VERSION 5.7 ;
  NOWIREEXTENSIONATPIN ON ;
  DIVIDERCHAR "/" ;
  BUSBITCHARS "[]" ;
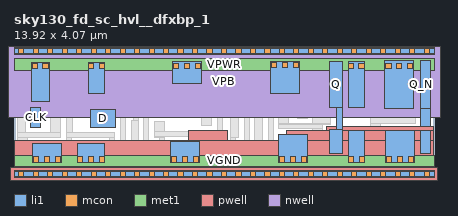
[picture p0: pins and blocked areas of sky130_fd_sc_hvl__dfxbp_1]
MACRO sky130_fd_sc_hvl__dfxbp_1
  CLASS BLOCK ;
  FOREIGN sky130_fd_sc_hvl__dfxbp_1 ;
  ORIGIN 0.000 0.000 ;
  SIZE 13.920 BY 4.070 ;
  PIN CLK
    ANTENNAGATEAREA 0.585000 ;
    PORT
      LAYER li1 ;
        RECT 0.560 1.550 0.890 2.220 ;
    END
  END CLK
  PIN D
    ANTENNAGATEAREA 0.420000 ;
    PORT
      LAYER li1 ;
        RECT 2.525 1.545 3.350 2.125 ;
    END
  END D
  PIN VGND
    USE GROUND ;
    PORT
      LAYER li1 ;
        RECT 0.620 0.365 1.570 1.020 ;
        RECT 2.100 0.365 2.990 1.015 ;
        RECT 5.185 0.365 6.135 1.065 ;
        RECT 8.775 0.365 9.725 1.325 ;
        RECT 11.070 0.365 11.625 1.485 ;
        RECT 12.315 0.365 13.265 1.485 ;
      LAYER mcon ;
        RECT 0.650 0.395 0.820 0.565 ;
        RECT 1.010 0.395 1.180 0.565 ;
        RECT 1.370 0.395 1.540 0.565 ;
        RECT 2.100 0.395 2.270 0.565 ;
        RECT 2.460 0.395 2.630 0.565 ;
        RECT 2.820 0.395 2.990 0.565 ;
        RECT 5.215 0.395 5.385 0.565 ;
        RECT 5.575 0.395 5.745 0.565 ;
        RECT 5.935 0.395 6.105 0.565 ;
        RECT 8.805 0.395 8.975 0.565 ;
        RECT 9.165 0.395 9.335 0.565 ;
        RECT 9.525 0.395 9.695 0.565 ;
        RECT 11.080 0.395 11.250 0.565 ;
        RECT 11.440 0.395 11.610 0.565 ;
        RECT 12.345 0.395 12.515 0.565 ;
        RECT 12.705 0.395 12.875 0.565 ;
        RECT 13.065 0.395 13.235 0.565 ;
      LAYER met1 ;
        RECT 0.000 0.255 13.920 0.625 ;
    END
  END VGND
  PIN VNB
    ANTENNADIFFAREA 2.366400 ;
    PORT
      LAYER pwell ;
        RECT 10.365 1.435 13.900 1.575 ;
        RECT 0.020 1.105 2.110 1.110 ;
        RECT 5.795 1.105 7.085 1.435 ;
        RECT 9.035 1.105 13.900 1.435 ;
        RECT 0.020 0.215 13.900 1.105 ;
        RECT -0.130 -0.215 14.050 0.215 ;
      LAYER li1 ;
        RECT 0.000 -0.085 13.920 0.085 ;
      LAYER mcon ;
        RECT 0.155 -0.085 0.325 0.085 ;
        RECT 0.635 -0.085 0.805 0.085 ;
        RECT 1.115 -0.085 1.285 0.085 ;
        RECT 1.595 -0.085 1.765 0.085 ;
        RECT 2.075 -0.085 2.245 0.085 ;
        RECT 2.555 -0.085 2.725 0.085 ;
        RECT 3.035 -0.085 3.205 0.085 ;
        RECT 3.515 -0.085 3.685 0.085 ;
        RECT 3.995 -0.085 4.165 0.085 ;
        RECT 4.475 -0.085 4.645 0.085 ;
        RECT 4.955 -0.085 5.125 0.085 ;
        RECT 5.435 -0.085 5.605 0.085 ;
        RECT 5.915 -0.085 6.085 0.085 ;
        RECT 6.395 -0.085 6.565 0.085 ;
        RECT 6.875 -0.085 7.045 0.085 ;
        RECT 7.355 -0.085 7.525 0.085 ;
        RECT 7.835 -0.085 8.005 0.085 ;
        RECT 8.315 -0.085 8.485 0.085 ;
        RECT 8.795 -0.085 8.965 0.085 ;
        RECT 9.275 -0.085 9.445 0.085 ;
        RECT 9.755 -0.085 9.925 0.085 ;
        RECT 10.235 -0.085 10.405 0.085 ;
        RECT 10.715 -0.085 10.885 0.085 ;
        RECT 11.195 -0.085 11.365 0.085 ;
        RECT 11.675 -0.085 11.845 0.085 ;
        RECT 12.155 -0.085 12.325 0.085 ;
        RECT 12.635 -0.085 12.805 0.085 ;
        RECT 13.115 -0.085 13.285 0.085 ;
        RECT 13.595 -0.085 13.765 0.085 ;
      LAYER met1 ;
        RECT 0.000 -0.115 13.920 0.115 ;
    END
  END VNB
  PIN VPB
    ANTENNADIFFAREA 2.366400 ;
    PORT
      LAYER nwell ;
        RECT -0.330 1.885 14.250 4.485 ;
      LAYER li1 ;
        RECT 0.000 3.985 13.920 4.155 ;
      LAYER mcon ;
        RECT 0.155 3.985 0.325 4.155 ;
        RECT 0.635 3.985 0.805 4.155 ;
        RECT 1.115 3.985 1.285 4.155 ;
        RECT 1.595 3.985 1.765 4.155 ;
        RECT 2.075 3.985 2.245 4.155 ;
        RECT 2.555 3.985 2.725 4.155 ;
        RECT 3.035 3.985 3.205 4.155 ;
        RECT 3.515 3.985 3.685 4.155 ;
        RECT 3.995 3.985 4.165 4.155 ;
        RECT 4.475 3.985 4.645 4.155 ;
        RECT 4.955 3.985 5.125 4.155 ;
        RECT 5.435 3.985 5.605 4.155 ;
        RECT 5.915 3.985 6.085 4.155 ;
        RECT 6.395 3.985 6.565 4.155 ;
        RECT 6.875 3.985 7.045 4.155 ;
        RECT 7.355 3.985 7.525 4.155 ;
        RECT 7.835 3.985 8.005 4.155 ;
        RECT 8.315 3.985 8.485 4.155 ;
        RECT 8.795 3.985 8.965 4.155 ;
        RECT 9.275 3.985 9.445 4.155 ;
        RECT 9.755 3.985 9.925 4.155 ;
        RECT 10.235 3.985 10.405 4.155 ;
        RECT 10.715 3.985 10.885 4.155 ;
        RECT 11.195 3.985 11.365 4.155 ;
        RECT 11.675 3.985 11.845 4.155 ;
        RECT 12.155 3.985 12.325 4.155 ;
        RECT 12.635 3.985 12.805 4.155 ;
        RECT 13.115 3.985 13.285 4.155 ;
        RECT 13.595 3.985 13.765 4.155 ;
      LAYER met1 ;
        RECT 0.000 3.955 13.920 4.185 ;
    END
  END VPB
  PIN VPWR
    USE POWER ;
    PORT
      LAYER li1 ;
        RECT 0.570 2.400 1.160 3.705 ;
        RECT 2.470 2.655 3.000 3.705 ;
        RECT 5.265 2.985 6.215 3.715 ;
        RECT 8.505 2.675 9.455 3.715 ;
        RECT 11.070 2.195 11.605 3.735 ;
        RECT 12.295 2.175 13.245 3.755 ;
      LAYER mcon ;
        RECT 0.600 3.505 0.770 3.675 ;
        RECT 0.960 3.505 1.130 3.675 ;
        RECT 2.470 3.505 2.640 3.675 ;
        RECT 2.830 3.505 3.000 3.675 ;
        RECT 5.295 3.505 5.465 3.675 ;
        RECT 5.655 3.505 5.825 3.675 ;
        RECT 6.015 3.505 6.185 3.675 ;
        RECT 8.535 3.515 8.705 3.685 ;
        RECT 8.895 3.515 9.065 3.685 ;
        RECT 9.255 3.515 9.425 3.685 ;
        RECT 11.070 3.505 11.240 3.675 ;
        RECT 11.430 3.505 11.600 3.675 ;
        RECT 12.325 3.505 12.495 3.675 ;
        RECT 12.685 3.505 12.855 3.675 ;
        RECT 13.045 3.505 13.215 3.675 ;
      LAYER met1 ;
        RECT 0.000 3.445 13.920 3.815 ;
    END
  END VPWR
  PIN Q
    ANTENNADIFFAREA 0.596250 ;
    PORT
      LAYER li1 ;
        RECT 10.455 2.195 10.890 3.735 ;
        RECT 10.685 1.465 10.890 2.195 ;
        RECT 10.455 0.675 10.890 1.465 ;
    END
  END Q
  PIN Q_N
    ANTENNADIFFAREA 0.626250 ;
    PORT
      LAYER li1 ;
        RECT 13.460 2.175 13.810 3.755 ;
        RECT 13.480 0.675 13.810 2.175 ;
    END
  END Q_N
  OBS
      LAYER li1 ;
        RECT 6.395 3.635 8.245 3.805 ;
        RECT 1.340 3.410 2.290 3.580 ;
        RECT 0.110 1.370 0.380 3.230 ;
        RECT 1.340 1.870 1.510 3.410 ;
        RECT 1.690 2.400 1.940 3.230 ;
        RECT 1.215 1.370 1.545 1.870 ;
        RECT 0.110 1.200 1.545 1.370 ;
        RECT 1.750 1.365 1.940 2.400 ;
        RECT 2.120 2.475 2.290 3.410 ;
        RECT 3.180 3.335 5.085 3.505 ;
        RECT 3.180 2.475 3.350 3.335 ;
        RECT 2.120 2.305 3.350 2.475 ;
        RECT 3.530 2.655 3.770 3.155 ;
        RECT 0.110 0.540 0.440 1.200 ;
        RECT 1.750 1.195 3.340 1.365 ;
        RECT 1.750 0.520 1.920 1.195 ;
        RECT 3.170 0.435 3.340 1.195 ;
        RECT 3.530 0.935 3.700 2.655 ;
        RECT 3.950 1.785 4.120 3.335 ;
        RECT 3.880 1.115 4.120 1.785 ;
        RECT 4.300 2.075 4.550 3.155 ;
        RECT 4.755 2.805 5.085 3.335 ;
        RECT 6.395 2.805 6.565 3.635 ;
        RECT 4.755 2.635 6.565 2.805 ;
        RECT 4.755 2.255 5.085 2.635 ;
        RECT 6.745 2.455 6.915 3.455 ;
        RECT 5.435 2.285 6.915 2.455 ;
        RECT 5.435 2.255 5.765 2.285 ;
        RECT 6.210 2.075 6.540 2.105 ;
        RECT 4.300 1.905 6.540 2.075 ;
        RECT 4.300 1.015 4.470 1.905 ;
        RECT 4.650 1.415 4.980 1.725 ;
        RECT 6.210 1.595 6.540 1.905 ;
        RECT 4.650 1.245 6.485 1.415 ;
        RECT 6.745 1.325 6.915 2.285 ;
        RECT 7.095 2.495 7.265 3.635 ;
        RECT 7.445 2.675 7.795 3.455 ;
        RECT 7.095 2.205 7.425 2.495 ;
        RECT 4.650 1.195 4.980 1.245 ;
        RECT 3.520 0.615 3.850 0.935 ;
        RECT 4.300 0.615 4.630 1.015 ;
        RECT 4.810 0.435 4.980 1.195 ;
        RECT 3.170 0.265 4.980 0.435 ;
        RECT 6.315 0.435 6.485 1.245 ;
        RECT 6.665 0.615 6.995 1.325 ;
        RECT 7.175 1.195 7.445 1.865 ;
        RECT 7.175 0.435 7.345 1.195 ;
        RECT 7.625 1.015 7.795 2.675 ;
        RECT 7.975 1.105 8.245 3.635 ;
        RECT 8.425 2.325 9.725 2.495 ;
        RECT 7.540 0.685 7.795 1.015 ;
        RECT 8.425 0.685 8.595 2.325 ;
        RECT 8.775 1.675 9.105 2.145 ;
        RECT 9.395 1.855 9.725 2.325 ;
        RECT 9.905 1.975 10.235 3.715 ;
        RECT 11.785 2.195 12.115 2.985 ;
        RECT 11.805 1.995 12.115 2.195 ;
        RECT 9.905 1.675 10.505 1.975 ;
        RECT 8.775 1.645 10.505 1.675 ;
        RECT 11.805 1.665 13.300 1.995 ;
        RECT 8.775 1.505 10.235 1.645 ;
        RECT 7.540 0.515 8.595 0.685 ;
        RECT 9.905 0.535 10.235 1.505 ;
        RECT 11.805 1.005 12.135 1.665 ;
        RECT 6.315 0.265 7.345 0.435 ;
  END
END sky130_fd_sc_hvl__dfxbp_1
END LIBRARY

